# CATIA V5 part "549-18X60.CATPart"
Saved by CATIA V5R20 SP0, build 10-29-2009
Part number: 549-18X60
Definition: NONE
Nomenclature: 549-18X60
Source: Unknown
Description: 549-18X60
Bounding box of the stored display mesh (mm): x 0 to 60, y -10.5 to 10.5, z -10.5 to 10.5
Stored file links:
  C:\Users\Utente\Desktop\IO LAVORO\3D X SITO CF\X SITO\PLASTICA\549\549-18X60.CATPart

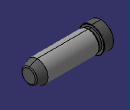
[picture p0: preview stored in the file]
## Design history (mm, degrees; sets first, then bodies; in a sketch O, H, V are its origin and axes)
Body1 "549-18X60" (main body)
  Solid1: solid without history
